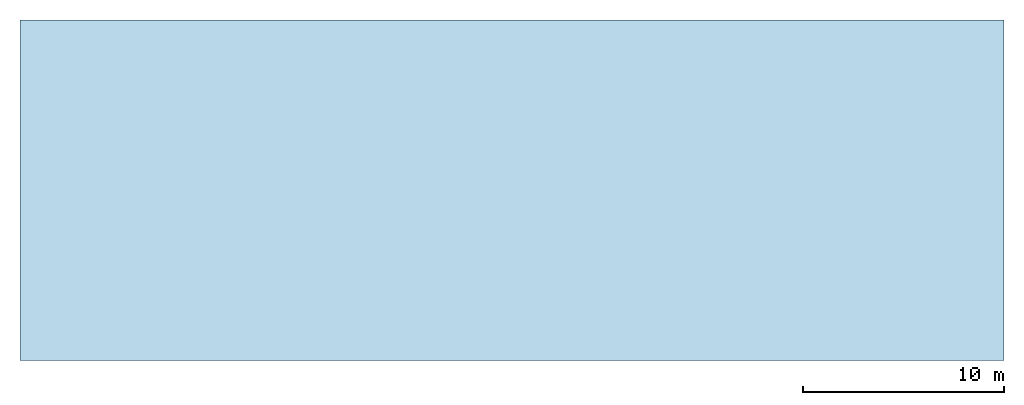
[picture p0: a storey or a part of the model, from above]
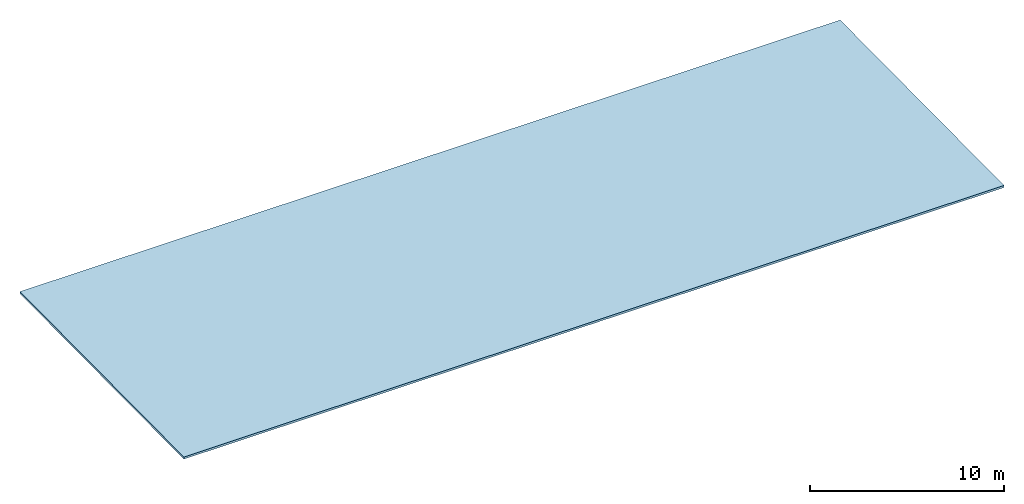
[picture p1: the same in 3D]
Properties of the parts of a building model (IFC4X3)

# File
Description: ViewDefinition [CoordinationView], RevitIdentifiers [VersionGUID: 392d5d86-4136-4b7f-a284-4d3e50420514, NumberOfSaves: 165], CoordinateReference [CoordinateBase: 共有座標, ProjectSite: 内部]
File name: 住木サンプルプラン3F_意匠_V24.ifc
Time: 2025-03-14T09:34:59+09:00
Written by: IfcOpenShell 0.8.0
Made in: Bonsai 0.8.0

# IfcProject, 123456
LongName: 標準参考テンプレート

# IfcSite, Default
RefLatitude: 35, 40, 59, 165954; RefLongitude: 139, 48, 33, 134765; RefElevation: 0 mm
Pset_SiteCommon - Reference: プロジェクト情報
Pset_SpaceCommon - Reference: プロジェクト情報; IsExternal: no

# IfcBuilding, 事務所ビル
LongName: 事務所ビル
Pset_BuildingCommon - Reference: プロジェクト情報; NumberOfStoreys: 6; IsLandmarked: no
Pset_BuildingElementProxyCommon - Reference: プロジェクト情報; IsExternal: no; sets with these values: 2
Pset_BuildingStoreyCommon - Reference: プロジェクト情報; AboveGround: no
Pset_BuildingSystemCommon - Reference: プロジェクト情報

# IfcBuildingStorey: レベル:標準上表記 (5)
In: 事務所ビル
Pset_BuildingStoreyCommon - AboveGround: no; Reference: 標準上表記
Pset_SpaceCommon - IsExternal: no; Reference: 標準上表記
Name | LongName | Elevation (mm)
1FL | 1FL | 0
2FL | 2FL | 4300
3FL | 3FL | 8000
RFL | RFL | 11470
最高高さ | 最高高さ | 12320

# IfcBuildingStorey: レベル:標準下表記, 設計GL
In: 事務所ビル
LongName: 設計GL; Elevation: -100 mm
Pset_BuildingStoreyCommon - Reference: 標準下表記; AboveGround: no
Pset_SpaceCommon - IsExternal: no; Reference: 標準下表記

# IfcSpace: EVホール 100:10737719, 100
In: 2FL
LongName: EVホール
Pset_SpaceCommon - IsExternal: no
Qto_SpaceBaseQuantities - NetPlannedArea: 17.3901 m2; Height: 2200 mm; FinishCeilingHeight: 670.56 mm
Pset_SpaceOccupancyRequirements - OccupancyType: 廊下
Pset_SpaceHVACDesign - MechanicalVentilation: no; HotWaterPresence: no; AirConditioning: no
Pset_SpaceLightingDesign - LightingFixtures: FRS15-322; NumberOfLightingFixtures: 3

# IfcSpace: EVホール 109:10737771, 109
In: 3FL
LongName: EVホール
Pset_SpaceCommon - IsExternal: no
Qto_SpaceBaseQuantities - NetPlannedArea: 17.3901 m2; Height: 2200 mm; FinishCeilingHeight: 670.56 mm
Pset_SpaceOccupancyRequirements - OccupancyType: 廊下
Pset_SpaceHVACDesign - MechanicalVentilation: no; HotWaterPresence: no; AirConditioning: no
Pset_SpaceLightingDesign - LightingFixtures: FRS15-322; NumberOfLightingFixtures: 3

# IfcSpace: EVホール 88:10716242, 88
In: 1FL
LongName: EVホール
Pset_SpaceCommon - IsExternal: no
Qto_SpaceBaseQuantities - NetPlannedArea: 17.3901 m2; Height: 2850 mm; FinishCeilingHeight: 868.68 mm
Pset_SpaceOccupancyRequirements - OccupancyType: 廊下
Pset_SpaceHVACDesign - MechanicalVentilation: no; HotWaterPresence: no; AirConditioning: no
Pset_SpaceLightingDesign - LightingFixtures: FRS15-322; NumberOfLightingFixtures: 3

# IfcSpace: WC 102:10737725, 102
In: 2FL
LongName: WC
Pset_SpaceCommon - IsExternal: no
Qto_SpaceBaseQuantities - NetPlannedArea: 14.9058 m2; Height: 2200 mm; FinishCeilingHeight: 670.56 mm
Pset_SpaceOccupancyRequirements - OccupancyType: 便所
Pset_SpaceHVACDesign - HotWaterPresence: no; AirConditioning: no; MechanicalVentilation: yes; VentilationName: FE-3
Pset_SpaceLightingDesign - LightingFixtures: FRS23-H321; NumberOfLightingFixtures: 7

# IfcSpace: WC 103:10737728, 103
In: 2FL
LongName: WC
Pset_SpaceCommon - IsExternal: no
Qto_SpaceBaseQuantities - NetPlannedArea: 14.9058 m2; Height: 2200 mm; FinishCeilingHeight: 670.56 mm
Pset_SpaceOccupancyRequirements - OccupancyType: 便所
Pset_SpaceHVACDesign - HotWaterPresence: no; AirConditioning: no; MechanicalVentilation: yes; VentilationName: FE-3
Pset_SpaceLightingDesign - LightingFixtures: FRS23-H321; NumberOfLightingFixtures: 7

# IfcSpace: WC 111:10737777, 111
In: 3FL
LongName: WC
Pset_SpaceCommon - IsExternal: no
Qto_SpaceBaseQuantities - NetPlannedArea: 14.9058 m2; Height: 2200 mm; FinishCeilingHeight: 670.56 mm
Pset_SpaceOccupancyRequirements - OccupancyType: 便所
Pset_SpaceHVACDesign - HotWaterPresence: no; AirConditioning: no; MechanicalVentilation: yes; VentilationName: FE-3
Pset_SpaceLightingDesign - LightingFixtures: FRS23-H321; NumberOfLightingFixtures: 7

# IfcSpace: WC 112:10737780, 112
In: 3FL
LongName: WC
Pset_SpaceCommon - IsExternal: no
Qto_SpaceBaseQuantities - NetPlannedArea: 14.9058 m2; Height: 2200 mm; FinishCeilingHeight: 670.56 mm
Pset_SpaceOccupancyRequirements - OccupancyType: 便所
Pset_SpaceHVACDesign - HotWaterPresence: no; AirConditioning: no; MechanicalVentilation: yes; VentilationName: FE-3
Pset_SpaceLightingDesign - LightingFixtures: FRS23-H321; NumberOfLightingFixtures: 7

# IfcSpace: WC 89:10716245, 89
In: 1FL
LongName: WC
Pset_SpaceCommon - IsExternal: no
Qto_SpaceBaseQuantities - NetPlannedArea: 14.9058 m2; Height: 2850 mm; FinishCeilingHeight: 868.68 mm
Pset_SpaceOccupancyRequirements - OccupancyType: 便所
Pset_SpaceHVACDesign - HotWaterPresence: no; AirConditioning: no; MechanicalVentilation: yes; VentilationName: FE-3
Pset_SpaceLightingDesign - LightingFixtures: FRS23-H321; NumberOfLightingFixtures: 7

# IfcSpace: WC 90:10716712, 90
In: 1FL
LongName: WC
Pset_SpaceCommon - IsExternal: no; Reference: WC 90
Qto_SpaceBaseQuantities - NetPlannedArea: 14.9058 m2; Height: 2850 mm; FinishCeilingHeight: 868.68 mm
Pset_SpaceOccupancyRequirements - OccupancyType: 便所
Pset_SpaceHVACDesign - HotWaterPresence: no; AirConditioning: no; MechanicalVentilation: yes; VentilationName: FE-3
Pset_SpaceLightingDesign - LightingFixtures: FRS23-H321; NumberOfLightingFixtures: 7

# IfcSpace: ロビー 91:10716755, 91
In: 1FL
LongName: ロビー
Pset_SpaceCommon - IsExternal: no
Qto_SpaceBaseQuantities - NetPlannedArea: 79.4976 m2; Height: 3280 mm; FinishCeilingHeight: 999.744 mm
Pset_SpaceOccupancyRequirements - OccupancyType: ロビー
Pset_SpaceHVACDesign - AirConditioning: yes; MechanicalVentilation: no; HotWaterPresence: no; AirHandlingName: PAC-1-4
Pset_SpaceLightingDesign - LightingFixtures: FRS15-322; NumberOfLightingFixtures: 11

# IfcSpace: 事務室 105:10737753, 105
In: 3FL
LongName: 事務室
Pset_SpaceCommon - IsExternal: no
Qto_SpaceBaseQuantities - NetPlannedArea: 700.573 m2; Height: 2680 mm; FinishCeilingHeight: 816.864 mm
Pset_SpaceOccupancyRequirements - OccupancyType: 事務室
Pset_SpaceHVACDesign - AirConditioning: yes; MechanicalVentilation: no; HotWaterPresence: yes; AirHandlingName: PAC-3-1
Pset_SpaceLightingDesign - LightingFixtures: FRS18L3V-322; NumberOfLightingFixtures: 169

# IfcSpace: 事務室 113:10955985, 113
In: 2FL
LongName: 事務室
Pset_SpaceCommon - IsExternal: no
Qto_SpaceBaseQuantities - NetPlannedArea: 274.414 m2; Height: 2680 mm; FinishCeilingHeight: 816.864 mm
Pset_SpaceOccupancyRequirements - OccupancyType: 事務室
Pset_SpaceHVACDesign - AirConditioning: yes; MechanicalVentilation: yes; HotWaterPresence: yes; AirHandlingName: PAC-2-2
Pset_SpaceLightingDesign - LightingFixtures: FRS18L3V-322; NumberOfLightingFixtures: 65

# IfcSpace: 事務室 94:10737700, 94
In: 2FL
LongName: 事務室
Pset_SpaceCommon - IsExternal: no
Qto_SpaceBaseQuantities - NetPlannedArea: 188.236 m2; Height: 2680 mm; FinishCeilingHeight: 816.864 mm
Pset_SpaceOccupancyRequirements - OccupancyType: 事務室
Pset_SpaceHVACDesign - AirConditioning: yes; MechanicalVentilation: no; HotWaterPresence: yes; AirHandlingName: PAC-2-3
Pset_SpaceLightingDesign - LightingFixtures: FRS18L3V-322; NumberOfLightingFixtures: 42

# IfcSpace: 事務室 96:10737707, 96
In: 2FL
LongName: 事務室
Pset_SpaceCommon - IsExternal: no
Qto_SpaceBaseQuantities - NetPlannedArea: 188.236 m2; Height: 2680 mm; FinishCeilingHeight: 816.864 mm
Pset_SpaceOccupancyRequirements - OccupancyType: 事務室
Pset_SpaceHVACDesign - AirConditioning: yes; MechanicalVentilation: no; HotWaterPresence: yes; AirHandlingName: PAC-2-1
Pset_SpaceLightingDesign - LightingFixtures: FRS18L3V-322; NumberOfLightingFixtures: 42

# IfcSpace: 倉庫 87:10716239, 87
In: 1FL
LongName: 倉庫
Pset_SpaceCommon - IsExternal: no
Qto_SpaceBaseQuantities - NetPlannedArea: 14.9058 m2; Height: 2850 mm; FinishCeilingHeight: 868.68 mm
Pset_SpaceOccupancyRequirements - OccupancyType: 更衣室又は倉庫
Pset_SpaceHVACDesign - HotWaterPresence: no; AirConditioning: no; MechanicalVentilation: yes; VentilationName: FE-3
Pset_SpaceLightingDesign - LightingFixtures: FRS23-H321; NumberOfLightingFixtures: 2

# IfcSpace: 店舗 82:10716224, 82
In: 1FL
LongName: 店舗
Pset_SpaceCommon - IsExternal: no
Qto_SpaceBaseQuantities - NetPlannedArea: 188.236 m2; Height: 3280 mm; FinishCeilingHeight: 999.744 mm
Pset_SpaceOccupancyRequirements - OccupancyType: 事務室
Pset_SpaceHVACDesign - AirConditioning: yes; MechanicalVentilation: no; HotWaterPresence: no; AirHandlingName: PAC-1-1
Pset_SpaceLightingDesign - LightingFixtures: FRS18L3V-322; NumberOfLightingFixtures: 42

# IfcSpace: 店舗 83:10716227, 83
In: 1FL
LongName: 店舗
Pset_SpaceCommon - IsExternal: no; Reference: 店舗 83
Pset_SpaceCoveringRequirements - FloorCovering: 大判タイル; WallCovering: 石こうボード t15; CeilingCovering: ロックウール化粧吸音板
Pset_SpaceHeaterTypeCommon - Reference: 店舗 83
Qto_SpaceBaseQuantities - NetPlannedArea: 200.971 m2; Height: 3280 mm; FinishCeilingHeight: 999.744 mm
Pset_SpaceOccupancyRequirements - OccupancyType: 事務室
Pset_SpaceHVACDesign - AirConditioning: yes; MechanicalVentilation: no; HotWaterPresence: no; AirHandlingName: PAC-1-2
Pset_SpaceLightingDesign - LightingFixtures: FRS18L3V-322; NumberOfLightingFixtures: 46

# IfcSpace: 店舗 84:10716230, 84
In: 1FL
LongName: 店舗
Pset_SpaceCommon - IsExternal: no; Reference: 店舗 84
Pset_SpaceCoveringRequirements - FloorCovering: 大判タイル; WallCovering: 石こうボード t15; CeilingCovering: ロックウール化粧吸音板
Pset_SpaceHeaterTypeCommon - Reference: 店舗 84
Qto_SpaceBaseQuantities - NetPlannedArea: 182.182 m2; Height: 3280 mm; FinishCeilingHeight: 999.744 mm
Pset_SpaceOccupancyRequirements - OccupancyType: 事務室
Pset_SpaceHVACDesign - AirConditioning: yes; MechanicalVentilation: no; HotWaterPresence: no; AirHandlingName: PAC-1-3
Pset_SpaceLightingDesign - LightingFixtures: FRS18L3V-322; NumberOfLightingFixtures: 42

# IfcSpace: 廊下 104:10737731, 104
In: 2FL
LongName: 廊下
Pset_SpaceCommon - IsExternal: no
Qto_SpaceBaseQuantities - NetPlannedArea: 49.686 m2; Height: 2200 mm; FinishCeilingHeight: 670.56 mm
Pset_SpaceOccupancyRequirements - OccupancyType: 廊下
Pset_SpaceHVACDesign - MechanicalVentilation: no; HotWaterPresence: no; AirConditioning: no
Pset_SpaceLightingDesign - LightingFixtures: FRS15-321; NumberOfLightingFixtures: 5

# IfcSpace: 廊下 86:10716236, 86
In: 1FL
LongName: 廊下
Pset_SpaceCommon - IsExternal: no
Qto_SpaceBaseQuantities - NetPlannedArea: 49.686 m2; Height: 2850 mm; FinishCeilingHeight: 868.68 mm
Pset_SpaceOccupancyRequirements - OccupancyType: 廊下
Pset_SpaceHVACDesign - MechanicalVentilation: no; HotWaterPresence: no; AirConditioning: no
Pset_SpaceLightingDesign - LightingFixtures: FRS15-321; NumberOfLightingFixtures: 5

# IfcSpace: 機械室 106:10737762, 106
In: 3FL
LongName: 機械室
Pset_SpaceCommon - IsExternal: no
Qto_SpaceBaseQuantities - NetPlannedArea: 29.8116 m2; Height: 2870 mm; FinishCeilingHeight: 874.776 mm
Pset_SpaceOccupancyRequirements - OccupancyType: 機械室
Pset_SpaceHVACDesign - HotWaterPresence: no; AirConditioning: no; MechanicalVentilation: yes; VentilationName: FS-1
Pset_SpaceLightingDesign - LightingFixtures: FRS23-H321; NumberOfLightingFixtures: 1

# IfcSpace: 機械室 85:10716233, 85
In: 1FL
LongName: 機械室
Pset_SpaceCommon - IsExternal: no
Qto_SpaceBaseQuantities - NetPlannedArea: 29.8116 m2; Height: 2850 mm; FinishCeilingHeight: 868.68 mm
Pset_SpaceOccupancyRequirements - OccupancyType: 機械室
Pset_SpaceHVACDesign - HotWaterPresence: no; AirConditioning: no; MechanicalVentilation: yes; VentilationName: FS-1
Pset_SpaceLightingDesign - LightingFixtures: FRS23-H321; NumberOfLightingFixtures: 1

# IfcSpace: 機械室 97:10737710, 97
In: 2FL
LongName: 機械室
Pset_SpaceCommon - IsExternal: no
Qto_SpaceBaseQuantities - NetPlannedArea: 29.8116 m2; Height: 2870 mm; FinishCeilingHeight: 874.776 mm
Pset_SpaceOccupancyRequirements - OccupancyType: 機械室
Pset_SpaceHVACDesign - HotWaterPresence: no; AirConditioning: no; MechanicalVentilation: yes; VentilationName: FS-1
Pset_SpaceLightingDesign - LightingFixtures: FRS23-H321; NumberOfLightingFixtures: 1

# IfcSpace: 給湯 107:10737765, 107
In: 3FL
LongName: 給湯
Pset_SpaceCommon - IsExternal: no
Qto_SpaceBaseQuantities - NetPlannedArea: 14.9058 m2; Height: 2200 mm; FinishCeilingHeight: 670.56 mm
Pset_SpaceOccupancyRequirements - OccupancyType: 湯沸室等
Pset_SpaceHVACDesign - HotWaterPresence: no; AirConditioning: no; MechanicalVentilation: yes; VentilationName: FE-2
Pset_SpaceLightingDesign - LightingFixtures: FRS23-H321; NumberOfLightingFixtures: 1

# IfcSpace: 給湯 98:10737713, 98
In: 2FL
LongName: 給湯
Pset_SpaceCommon - IsExternal: no
Qto_SpaceBaseQuantities - NetPlannedArea: 14.9058 m2; Height: 2200 mm; FinishCeilingHeight: 670.56 mm
Pset_SpaceOccupancyRequirements - OccupancyType: 湯沸室等
Pset_SpaceHVACDesign - HotWaterPresence: no; AirConditioning: no; MechanicalVentilation: yes; VentilationName: FE-2
Pset_SpaceLightingDesign - LightingFixtures: FRS23-H321; NumberOfLightingFixtures: 1

# IfcSpace: 階段 101:10737722, 101
In: 2FL
LongName: 階段
Pset_SpaceCommon - IsExternal: no
Qto_SpaceBaseQuantities - NetPlannedArea: 14.9058 m2; Height: 3700 mm
Pset_SpaceHVACDesign - MechanicalVentilation: no; HotWaterPresence: no; AirConditioning: no

# IfcSpace: 階段 108:10737768, 108
In: 3FL
LongName: 階段
Pset_SpaceCommon - IsExternal: no
Qto_SpaceBaseQuantities - NetPlannedArea: 14.9058 m2; Height: 2200 mm
Pset_SpaceHVACDesign - MechanicalVentilation: no; HotWaterPresence: no; AirConditioning: no

# IfcSpace: 階段 110:10737774, 110
In: 3FL
LongName: 階段
Pset_SpaceCommon - IsExternal: no
Qto_SpaceBaseQuantities - NetPlannedArea: 14.9058 m2; Height: 2200 mm
Pset_SpaceHVACDesign - MechanicalVentilation: no; HotWaterPresence: no; AirConditioning: no

# IfcSpace: 階段 92:10719681, 92
In: 1FL
LongName: 階段
Pset_SpaceCommon - IsExternal: no
Qto_SpaceBaseQuantities - NetPlannedArea: 14.9058 m2; Height: 4300 mm
Pset_SpaceHVACDesign - MechanicalVentilation: no; HotWaterPresence: no; AirConditioning: no

# IfcSpace: 階段 93:10719684, 93
In: 1FL
LongName: 階段
Pset_SpaceCommon - IsExternal: no
Qto_SpaceBaseQuantities - NetPlannedArea: 14.9058 m2; Height: 4300 mm
Pset_SpaceHVACDesign - MechanicalVentilation: no; HotWaterPresence: no; AirConditioning: no

# IfcSpace: 階段 99:10737716, 99
In: 2FL
LongName: 階段
Pset_SpaceCommon - IsExternal: no
Qto_SpaceBaseQuantities - NetPlannedArea: 14.9058 m2; Height: 3700 mm
Pset_SpaceHVACDesign - MechanicalVentilation: no; HotWaterPresence: no; AirConditioning: no

# IfcCovering: 天井:(仕上)GB-Rt12.5+DR t12 (38)
Type - PredefinedType: CEILING
Type - Pset_CoveringCommon - IsExternal: no
Material: <Unnamed> 10 mm
Name (天井:(仕上)GB-Rt12.5+DR t12:...) | In | Pset_CoveringCommon, Reference = Pset_EnvironmentalImpactIndicators, Reference
10720730 | 1FL | (仕上)GB-Rt12.5+DR t12
10720965 | 82
10726489 | 83
10727184 | 84
10728089 | 91
10728653 | 1FL | (仕上)GB-Rt12.5+DR t12
10728711 | 1FL | (仕上)GB-Rt12.5+DR t12
10728745 | 1FL | (仕上)GB-Rt12.5+DR t12
10728777 | 86
10728810 | 85
10728850 | 87
10728890 | 88
10728924 | 1FL | (仕上)GB-Rt12.5+DR t12
10728957 | 90
10728990 | 89
10729932 | 2FL | (仕上)GB-Rt12.5+DR t12
10729939 | 94
10729950 | 2FL | (仕上)GB-Rt12.5+DR t12
10729975 | 2FL | (仕上)GB-Rt12.5+DR t12
10729982 | 2FL | (仕上)GB-Rt12.5+DR t12
10729996 | 104
10730003 | 2FL | (仕上)GB-Rt12.5+DR t12
10730010 | 98 | (仕上)GB-Rt12.5+DR t12
10730017 | 100 | (仕上)GB-Rt12.5+DR t12
10730024 | 2FL | (仕上)GB-Rt12.5+DR t12
10730031 | 102 | (仕上)GB-Rt12.5+DR t12
10730038 | 103 | (仕上)GB-Rt12.5+DR t12
10730186 | 96
10733353 | 3FL | (仕上)GB-Rt12.5+DR t12
10733360 | 3FL | (仕上)GB-Rt12.5+DR t12
10733371 | 3FL | (仕上)GB-Rt12.5+DR t12
10733399 | 3FL | (仕上)GB-Rt12.5+DR t12
10733406 | 107 | (仕上)GB-Rt12.5+DR t12
10733413 | 109 | (仕上)GB-Rt12.5+DR t12
10733420 | 3FL | (仕上)GB-Rt12.5+DR t12
10733427 | 111 | (仕上)GB-Rt12.5+DR t12
10733434 | 112 | (仕上)GB-Rt12.5+DR t12
10733441 | 3FL | (仕上)GB-Rt12.5+DR t12

# IfcDoor: シャッター - 上下開閉式:シャッター - 上下開閉式 H2200 (3)
Type - PredefinedType: DOOR; ParameterTakesPrecedence: no; Material: <Unnamed>
Type - Pset_DoorCommon - IsExternal: no; HasLouver: no
OverallHeight: 2200 mm; OverallWidth: 1530 mm
Name (シャッター - 上下開閉式:シャッター - 上下開閉式 H2200:...) | In
10780350 | 1FL
10780501 | 1FL
10780597 | 2FL

# IfcDoor: ドア-開口部:1017 x 2100mm (3)
Type - PredefinedType: DOOR; ParameterTakesPrecedence: no; Material: <Unnamed>
Type - Pset_DoorCommon - IsExternal: no; HasLouver: no
OverallHeight: 2100 mm; OverallWidth: 1017 mm
Pset_DoorCommon - Reference: 1017 x 2100mm
Pset_EnvironmentalImpactIndicators - Reference: 1017 x 2100mm
Name (ドア-開口部:1017 x 2100mm:...) | In
10718628 | 1FL
10729121 | 2FL
10731907 | 3FL

# IfcDoor: ドア-開口部:2275 x 2100mm (3)
Type - PredefinedType: DOOR; ParameterTakesPrecedence: no; Material: <Unnamed>
Type - Pset_DoorCommon - IsExternal: no; HasLouver: no
OverallHeight: 2100 mm; OverallWidth: 2275 mm
Pset_DoorCommon - Reference: 2275 x 2100mm
Pset_EnvironmentalImpactIndicators - Reference: 2275 x 2100mm
Name (ドア-開口部:2275 x 2100mm:...) | In
10718684 | 1FL
10729122 | 2FL
10731908 | 3FL

# IfcDoor: 自動ドア - 両引き - 框:鋼製戸 - 両引き - 框, 自動ドア - 両引き - 框:鋼製戸 - 両引き - 框:10703156
In: 1FL
Type - PredefinedType: DOOR; ParameterTakesPrecedence: no; Material: <Unnamed> (2), ガラス
Type - Pset_DoorCommon - IsExternal: no; HasLouver: no
OverallHeight: 2440 mm; OverallWidth: 5280 mm; Material: <Unnamed>, ガラス

# IfcDoor: 自動ドア - 片引き - 框:自動ドア - 片引き - 框 (3)
In: 1FL
Type - PredefinedType: DOOR; ParameterTakesPrecedence: no; Material: <Unnamed> (2), ガラス
Type - Pset_DoorCommon - IsExternal: no; ThermalTransmittance: 3.6886 kg/K/s3; HasLouver: no
Type - Pset_DoorWindowGlazingType - SolarHeatGainTransmittance: 0.78 kg/K/s3
Material: <Unnamed>, ガラス
Name (自動ドア - 片引き - 框:自動ドア - 片引き - 框:...) | OverallHeight (mm) | OverallWidth (mm)
10702319 | 2040 | 1680
10962794 | 2440 | 3480
10963158 | 2440 | 3480

# IfcDoor: 鋼製_一般枠_片開き 1:鋼製_一般枠_片開き 1 (6)
Type - PredefinedType: DOOR; OperationType: SINGLE_SWING_LEFT; ParameterTakesPrecedence: no; Material: 金属 - アルミニウム (2), 塗装 - 白, ガラス
Type - 鋼製_一般枠_片開き 1:鋼製_一般枠_片開き 1:10708855:1 - PanelOperation: SWINGING
Type - Pset_DoorCommon - IsExternal: no; HasLouver: no
OverallHeight: 2140 mm; OverallWidth: 980 mm; Material: 金属 - アルミニウム, 塗装 - 白, ガラス
Name (鋼製_一般枠_片開き 1:鋼製_一般枠_片開き 1:...) | In
10708855 | 1FL
10709950 | 1FL
10729116 | 2FL
10729119 | 2FL
10731902 | 3FL
10731905 | 3FL

# IfcDoor: 鋼製_一般枠_片開き 1:鋼製_一般枠_片開き 1 (6)
Type - PredefinedType: DOOR; OperationType: SINGLE_SWING_RIGHT; ParameterTakesPrecedence: no; Material: 金属 - アルミニウム (2), 塗装 - 白, ガラス
Type - 鋼製_一般枠_片開き 1:鋼製_一般枠_片開き 1:10709358:1 - PanelOperation: SWINGING
Type - Pset_DoorCommon - IsExternal: no; HasLouver: no
OverallHeight: 2140 mm; OverallWidth: 980 mm; Material: 金属 - アルミニウム, 塗装 - 白, ガラス
Name (鋼製_一般枠_片開き 1:鋼製_一般枠_片開き 1:...) | In
10709358 | 1FL
10709926 | 1FL
10729117 | 2FL
10729118 | 2FL | Pset_DoorCommon - Reference: 鋼製_一般枠_片開き 1; Pset_EnvironmentalImpactIndicators - Reference: 鋼製_一般枠_片開き 1
10731903 | 3FL
10731904 | 3FL

# IfcDoor: 鋼製_大枠_両開き_框:1400x2000 (14)
Type - PredefinedType: DOOR; ParameterTakesPrecedence: no; Material: ステンレス, 塗装 - 白 (2), ガラス
Type - 鋼製_大枠_両開き_框:1400x2000:10688236:1 - PanelOperation: SWINGING
Type - Pset_DoorCommon - IsExternal: no; HasLouver: no
OverallHeight: 2055 mm; OverallWidth: 1480 mm; Material: ステンレス, 塗装 - 白, ガラス
Name (鋼製_大枠_両開き_框:1400x2000:...) | In
10688236 | 1FL
10688547 | 1FL
10689308 | 1FL
10689426 | 1FL
10704238 | 1FL
10704292 | 1FL
10729101 | 2FL
10729102 | 2FL
10729103 | 2FL
10729104 | 2FL
10729112 | 2FL
10729113 | 2FL
10731898 | 3FL
10731899 | 3FL

# IfcDoor: 鋼製_大枠_両開き_框:1400x2000 (3)
In: 1FL
Type - PredefinedType: DOOR; ParameterTakesPrecedence: no; Material: ステンレス, 塗装 - 白 (2), ガラス
Type - 鋼製_大枠_両開き_框:1400x2000:10702580:1 - PanelOperation: SWINGING
Type - Pset_DoorCommon - IsExternal: no; HasLouver: no
OverallHeight: 2055 mm; OverallWidth: 1480 mm; Material: ステンレス, 塗装 - 白, ガラス
Name (鋼製_大枠_両開き_框:1400x2000:...)
10702580
10704753
10704847

# IfcDoor: 鋼製_大枠_両開き_框:1400x2000, 鋼製_大枠_両開き_框:1400x2000:10785605
In: 設計GL
Type - PredefinedType: DOOR; ParameterTakesPrecedence: no; Material: ステンレス, 塗装 - 白 (2), ガラス
Type - 鋼製_大枠_両開き_框:1400x2000:10785605:1 - PanelOperation: SWINGING
Type - Pset_DoorCommon - IsExternal: no; HasLouver: no
OverallHeight: 2055 mm; OverallWidth: 1480 mm; Material: ステンレス, 塗装 - 白, ガラス

# IfcDoor: 鋼製_大枠_片開き_窓付:700x2100, 鋼製_大枠_片開き_窓付:700x2100:10786122
In: 1FL
Type - PredefinedType: DOOR; OperationType: SINGLE_SWING_LEFT; ParameterTakesPrecedence: no; Material: ステンレス, 塗装 - 白 (2), ガラス
Type - 鋼製_大枠_片開き_窓付:700x2100:10786122:1 - PanelOperation: SWINGING
Type - Pset_DoorCommon - IsExternal: no; HasLouver: no
OverallHeight: 2155 mm; OverallWidth: 780 mm; Material: ステンレス, 塗装 - 白, ガラス

# IfcDoor: 鋼製_大枠_片開き_窓付:700x2100, 鋼製_大枠_片開き_窓付:700x2100:10785387
In: 1FL
Type - PredefinedType: DOOR; OperationType: SINGLE_SWING_RIGHT; ParameterTakesPrecedence: no; Material: ステンレス, 塗装 - 白 (2), ガラス
Type - 鋼製_大枠_片開き_窓付:700x2100:10785387:1 - PanelOperation: SWINGING
Type - Pset_DoorCommon - IsExternal: no; HasLouver: no
OverallHeight: 2155 mm; OverallWidth: 780 mm; Material: ステンレス, 塗装 - 白, ガラス

# IfcOpeningElement (178)
PredefinedType: OPENING
Name | In
標準壁:(基礎梁)RC_w240h1000:10638460 | 1FL | Pset_EnvironmentalImpactIndicators - Reference: 700x2100; sets with these values: 2
標準壁:(基礎梁)RC_w240h1000:10638760 | 1FL | Pset_EnvironmentalImpactIndicators - Reference: 1400x2000; sets with these values: 2
標準壁:(基礎梁)RC_w240h1000:10639040 | 1FL | Pset_EnvironmentalImpactIndicators - Reference: 1400x2000; sets with these values: 2
標準壁:(基礎梁)RC_w240h650:10640903:1 | 1FL | Pset_EnvironmentalImpactIndicators - Reference: (基礎梁)RC_w240h650; sets with these values: 2
標準壁:(基礎梁)RC_w210h650:10643982:1 | 1FL | Pset_EnvironmentalImpactIndicators - Reference: (基礎梁)RC_w210h650; sets with these values: 2
標準壁:(基礎梁)RC_w210h650:10644302:1 | 1FL | Pset_EnvironmentalImpactIndicators - Reference: (基礎梁)RC_w210h650; sets with these values: 2
標準壁:(基礎梁)RC_w210h650:10644448:1 | 1FL | Pset_EnvironmentalImpactIndicators - Reference: (基礎梁)RC_w210h650; sets with these values: 2
標準壁:(基礎梁)RC_w210h650:10644556:1 | 1FL | Pset_EnvironmentalImpactIndicators - Reference: (基礎梁)RC_w210h650; sets with these values: 2
標準壁:(基礎梁)RC_w210h650:10644740:1 | 1FL | Pset_EnvironmentalImpactIndicators - Reference: (基礎梁)RC_w210h650; sets with these values: 2
2 x 標準壁:(基礎梁)RC_w210h1000:10645130 | 1FL | Pset_EnvironmentalImpactIndicators - Reference: 6 人乗; sets with these values: 2
標準壁:外装材46_構造用合板12_木240_構造用合板12_GB-R15:10672847 | 1FL | Pset_EnvironmentalImpactIndicators - Reference: 1450x2700; sets with these values: 2
標準壁:外装材46_構造用合板12_木240_構造用合板12_GB-R15:10673549 | 1FL | Pset_EnvironmentalImpactIndicators - Reference: 鋼製戸 - 両引き - 框; sets with these values: 2
標準壁:外装材46_構造用合板12_木240_構造用合板12_GB-R15:10674468 | 1FL | Pset_EnvironmentalImpactIndicators - Reference: 1450x2700; sets with these values: 2
2 x 標準壁:外装材46_構造用合板12_木240_構造用合板12_GB-R15:10674640 | 1FL | Pset_EnvironmentalImpactIndicators - Reference: 700x2100; sets with these values: 2
標準壁:外装材46_構造用合板12_木240_構造用合板12_GB-R15:10674640 | 1FL | Pset_EnvironmentalImpactIndicators - Reference: 1400x2000; sets with these values: 2
標準壁:GB-R15_構造用合板12_木210_構造用合板12_GB-R15:10676044 | 1FL | Pset_EnvironmentalImpactIndicators - Reference: 1400x2000; sets with these values: 2
2 x 標準壁:GB-R15_構造用合板12_木210_構造用合板12_GB-R15:10676202 | 1FL | Pset_EnvironmentalImpactIndicators - Reference: 1400x2000; sets with these values: 2
標準壁:GB-R15_構造用合板12_木210_構造用合板12_GB-R15:10676344 | 1FL | Pset_EnvironmentalImpactIndicators - Reference: 1400x2000; sets with these values: 2
2 x 標準壁:GB-R15_構造用合板12_木210_構造用合板12_GB-R15:10677149 | 1FL | Pset_EnvironmentalImpactIndicators - Reference: 2275 x 2100mm; sets with these values: 2
5 x 床:タイル20_モルタル30_スラブ200:1092007 | 1FL | Pset_EnvironmentalImpactIndicators - Reference: タイル20_モルタル30_スラブ200; sets with these values: 2
標準壁:GB-R15_構造用合板12_木210_構造用合板12_GB-R15:10684239 | 1FL | Pset_EnvironmentalImpactIndicators - Reference: 鋼製_一般枠_片開き 1; sets with these values: 2
標準壁:GB-R15_構造用合板12_木210_構造用合板12_GB-R15:10684438 | 1FL | Pset_EnvironmentalImpactIndicators - Reference: 2275 x 2100mm; sets with these values: 2
2 x 標準壁:GB-R15_構造用合板12_木210_構造用合板12_GB-R15:10684519 | 1FL | Pset_EnvironmentalImpactIndicators - Reference: 鋼製_一般枠_片開き 1; sets with these values: 2
2 x 標準壁:(内壁)木210/構造用合板12/GB-R15)/*:10725627 | 1FL | Pset_EnvironmentalImpactIndicators - Reference: 6 人乗; sets with these values: 2
2 x 標準壁:GB-R15_構造用合板12_木210_構造用合板12_GB-R15:10729093 | 2FL | Pset_EnvironmentalImpactIndicators - Reference: 2275 x 2100mm; sets with these values: 2
標準壁:GB-R15_構造用合板12_木210_構造用合板12_GB-R15:10729097 | 2FL | Pset_EnvironmentalImpactIndicators - Reference: 鋼製_一般枠_片開き 1; sets with these values: 2
標準壁:GB-R15_構造用合板12_木210_構造用合板12_GB-R15:10729098 | 2FL | Pset_EnvironmentalImpactIndicators - Reference: 2275 x 2100mm; sets with these values: 2
5 x 床:複層床:10729757 | 2FL | Pset_EnvironmentalImpactIndicators - Reference: 複層床; sets with these values: 2
2 x 標準壁:外装材46_構造用合板12_木240_構造用合板12_GB-R15:10731865 | 3FL | Pset_EnvironmentalImpactIndicators - Reference: 1450x2600; sets with these values: 2
標準壁:外装材46_構造用合板12_木240_構造用合板12_GB-R15:10731869 | 3FL | Pset_EnvironmentalImpactIndicators - Reference: 1450x2600; sets with these values: 2
標準壁:GB-R15_構造用合板12_木210_構造用合板12_GB-R15:10731879 | 3FL | Pset_EnvironmentalImpactIndicators - Reference: 2275 x 2100mm; sets with these values: 2
2 x 床:複層床:10729757 | 3FL | Pset_EnvironmentalImpactIndicators - Reference: 複層床; sets with these values: 2
2 x 標準壁:(内壁)木210/構造用合板12/GB-R15)/*:10737047 | 2FL | Pset_EnvironmentalImpactIndicators - Reference: 6 人乗; sets with these values: 2
標準壁:外装材46_構造用合板12_木240_構造用合板12_GB-R15:10739789 | 3FL | Pset_EnvironmentalImpactIndicators - Reference: 540x2700; sets with these values: 2
標準壁:GB-R15:10970786:1 | 1FL | Pset_EnvironmentalImpactIndicators - Reference: GB-R15; sets with these values: 2
標準壁:GB-R15:10971127:1 | 2FL | Pset_EnvironmentalImpactIndicators - Reference: GB-R15; sets with these values: 2
自動ドア - 両引き - 框:鋼製戸 - 両引き - 框:10703156:1 | 1FL
鋼製_大枠_片開き_窓付:700x2100:10785387:1 | 1FL
鋼製_大枠_両開き_框:1400x2000:10785605:1 | 1FL
鋼製_大枠_片開き_窓付:700x2100:10786122:1 | 1FL
鋼製_大枠_両開き_框:1400x2000:10704753:1 | 1FL
鋼製_大枠_両開き_框:1400x2000:10704847:1 | 1FL
6 x 標準壁:外装材46_構造用合板12_木240_構造用合板12_GB-R15:10673549 | 1FL
自動ドア - 片引き - 框:自動ドア - 片引き - 框:10962794:1 | 1FL
自動ドア - 片引き - 框:自動ドア - 片引き - 框:10963158:1 | 1FL
自動ドア - 片引き - 框:自動ドア - 片引き - 框:10702319:1 | 1FL
鋼製_大枠_両開き_框:1400x2000:10702580:1 | 1FL
8 x 標準壁:外装材46_構造用合板12_木240_構造用合板12_GB-R15:10674640 | 1FL
シャッター - 上下開閉式:シャッター - 上下開閉式 H2200:10780350:1 | 1FL
シャッター - 上下開閉式:シャッター - 上下開閉式 H2200:10780501:1 | 1FL
鋼製_大枠_両開き_框:1400x2000:10688236:1 | 1FL
鋼製_大枠_両開き_框:1400x2000:10689308:1 | 1FL
鋼製_大枠_両開き_框:1400x2000:10689426:1 | 1FL
鋼製_大枠_両開き_框:1400x2000:10688547:1 | 1FL
鋼製_大枠_両開き_框:1400x2000:10704238:1 | 1FL
鋼製_大枠_両開き_框:1400x2000:10704292:1 | 1FL
ドア-開口部:1017 x 2100mm:10718628:1 | 1FL
鋼製_一般枠_片開き 1:鋼製_一般枠_片開き 1:10708855:1 | 1FL
ドア-開口部:2275 x 2100mm:10718684:1 | 1FL
鋼製_一般枠_片開き 1:鋼製_一般枠_片開き 1:10709358:1 | 1FL
鋼製_一般枠_片開き 1:鋼製_一般枠_片開き 1:10709926:1 | 1FL
鋼製_一般枠_片開き 1:鋼製_一般枠_片開き 1:10709950:1 | 1FL
3 x 標準壁:外装材46_構造用合板12_木240_構造用合板12_GB-R15:10729079 | 2FL
13 x 標準壁:外装材46_構造用合板12_木240_構造用合板12_GB-R15:10729082 | 2FL
3 x 標準壁:外装材46_構造用合板12_木240_構造用合板12_GB-R15:10729083 | 2FL
シャッター - 上下開閉式:シャッター - 上下開閉式 H2200:10780597:1 | 2FL
12 x 標準壁:外装材46_構造用合板12_木240_構造用合板12_GB-R15:10729086 | 2FL
鋼製_大枠_両開き_框:1400x2000:10729101:1 | 2FL
鋼製_大枠_両開き_框:1400x2000:10729103:1 | 2FL
鋼製_大枠_両開き_框:1400x2000:10729104:1 | 2FL
鋼製_大枠_両開き_框:1400x2000:10729102:1 | 2FL
鋼製_大枠_両開き_框:1400x2000:10729112:1 | 2FL
鋼製_大枠_両開き_框:1400x2000:10729113:1 | 2FL
ドア-開口部:1017 x 2100mm:10729121:1 | 2FL
鋼製_一般枠_片開き 1:鋼製_一般枠_片開き 1:10729116:1 | 2FL
ドア-開口部:2275 x 2100mm:10729122:1 | 2FL
鋼製_一般枠_片開き 1:鋼製_一般枠_片開き 1:10729117:1 | 2FL
鋼製_一般枠_片開き 1:鋼製_一般枠_片開き 1:10729118:1 | 2FL
鋼製_一般枠_片開き 1:鋼製_一般枠_片開き 1:10729119:1 | 2FL
4 x 標準壁:外装材46_構造用合板12_木240_構造用合板12_GB-R15:10731865 | 3FL
14 x 標準壁:外装材46_構造用合板12_木240_構造用合板12_GB-R15:10731868 | 3FL
4 x 標準壁:外装材46_構造用合板12_木240_構造用合板12_GB-R15:10731869 | 3FL
鋼製_大枠_両開き_框:1400x2000:10731898:1 | 3FL
鋼製_大枠_両開き_框:1400x2000:10731899:1 | 3FL
ドア-開口部:1017 x 2100mm:10731907:1 | 3FL
鋼製_一般枠_片開き 1:鋼製_一般枠_片開き 1:10731902:1 | 3FL
ドア-開口部:2275 x 2100mm:10731908:1 | 3FL
鋼製_一般枠_片開き 1:鋼製_一般枠_片開き 1:10731903:1 | 3FL
鋼製_一般枠_片開き 1:鋼製_一般枠_片開き 1:10731904:1 | 3FL
鋼製_一般枠_片開き 1:鋼製_一般枠_片開き 1:10731905:1 | 3FL
12 x 標準壁:外装材46_構造用合板12_木240_構造用合板12_GB-R15:10739789 | 3FL

# IfcSlab: 床:タイル20_モルタル30_スラブ200, 床:タイル20_モルタル30_スラブ200:10677755
In: 1FL
Type - PredefinedType: FLOOR; Material: <Unnamed> 200 mm
Type - Pset_SlabCommon - IsExternal: no
Type - Qto_SlabBaseQuantities - Depth: 200 mm
Qto_SlabBaseQuantities - NetArea: 804.585 m2; NetVolume: 160.917 m3

# IfcSlab: 床:複層床 (2)
Type - PredefinedType: FLOOR; Material: <Unnamed> 106 mm, 硬質ウレタンフォーム 100 mm, 合板 24 mm
Type - Pset_SlabCommon - IsExternal: no
Type - Qto_SlabBaseQuantities - Depth: 230 mm
Name (床:複層床:...) | In | NetArea (m2) | NetVolume (m3)
10729427 | 2FL | 771.885 | 177.534
10731914 | 3FL | 783.328 | 180.166

# IfcSlab: 標準屋根:(屋根)シート防水, 標準屋根:(屋根)シート防水:10733734
In: RFL
Type - Pset_SlabCommon - IsExternal: yes
Type - Qto_SlabBaseQuantities - Depth: 133.5 mm
Material: アスファルト類 3 mm, 硬質ウレタンフォーム 70 mm, 合板 12 mm, 非密閉中空層 30 mm, せっこうボード 9.5 mm, ロックウール化粧吸音板 9 mm; アスファルト類 3 mm, 硬質ウレタンフォーム 70 mm, 合板 12 mm, 非密閉中空層 30 mm, せっこうボード 9.5 mm, ロックウール化粧吸音板 9 mm
Pset_SlabCommon - Reference: (屋根)シート防水
Qto_SlabBaseQuantities - NetArea: 826.665 m2; NetVolume: 110.36 m3

# IfcWall: 標準壁:(内壁)木210/構造用合板12/GB-R15)/* (3)
Type - PredefinedType: STANDARD; Material: 天然木材 210 mm, <Unnamed> 12 mm, <Unnamed> 15 mm
Type - Pset_WallCommon - IsExternal: no; isExternal: no
Type - Qto_WallBaseQuantities - Width: 237 mm
Qto_WallBaseQuantities - Length: 5475.5 mm
Name (標準壁:(内壁)木210/構造用合板12/GB-R15)/*:...) | In | NetSideArea (m2) | NetVolume (m3)
10725627 | 1FL | 16.7481 | 3.9693
10731910 | 3FL | 17.9781 | 4.2608
10737047 | 2FL | 14.8983 | 3.5309

# IfcWall: 標準壁:(基礎梁)RC_w210h1000 (16)
In: 1FL
Type - PredefinedType: STANDARD; Material: *コンクリート 210 mm
Type - Pset_WallCommon - IsExternal: yes; isExternal: yes
Type - Qto_WallBaseQuantities - Width: 210 mm
Pset_EnvironmentalImpactIndicators - Reference: (基礎梁)RC_w210h1000; sets with these values: 2
Pset_WallCommon - ExtendToStructure: no; LoadBearing: yes; Reference: (基礎梁)RC_w210h1000
Name (標準壁:(基礎梁)RC_w210h1000:...) | NetSideArea (m2) | Length (mm) | NetVolume (m3)
10641416 | 5.38725 | 5460 | 1.13132
10641685 | 3.535 | 3640 | 0.74235
10641852 | 5.445 | 5565 | 1.14345
10642087 | 5.445 | 5460 | 1.14345
10642149 | 0.805 | 910 | 0.16905
10642448 | 5.445 | 5460 | 1.14345
10642514 | 0.805 | 910 | 0.16905
10645130 | 4.4214 | 5460 | 0.928494
10645255 | 3.85725 | 3810 | 0.810022
10645477 | 5.235 | 5460 | 1.09935
10645581 | 5.235 | 5460 | 1.09935
10645728 | 0.8995 | 910 | 0.188895
10645901 | 1.715 | 1820 | 0.36015
10646037 | 1.7 | 1820 | 0.357
10647090 | 1.82 | 1820 | 0.3822
10647203 | 5.445 | 5565 | 1.14345

# IfcWall: 標準壁:(基礎梁)RC_w210h650 (18)
In: 1FL
Type - PredefinedType: STANDARD; Material: *コンクリート 210 mm
Type - Pset_WallCommon - IsExternal: yes; isExternal: yes
Type - Qto_WallBaseQuantities - Width: 210 mm
Pset_EnvironmentalImpactIndicators - Reference: (基礎梁)RC_w210h650; sets with these values: 2
Pset_WallCommon - ExtendToStructure: no; Reference: (基礎梁)RC_w210h650; LoadBearing: yes
Name (標準壁:(基礎梁)RC_w210h650:...) | NetSideArea (m2) | Length (mm) | NetVolume (m3)
10640784 | 9.36925 | 17290 | 1.96754
10641139 | 0.935 | 1700 | 0.19635
10643982 | 9.23725 | 17290 | 1.93982
10644136 | 0.87725 | 1595 | 0.184223
10644302 | 6.358 | 11830 | 1.33518
10644448 | 6.2425 | 11695 | 1.31092
10644556 | 6.2425 | 11830 | 1.31092
10644740 | 6.2425 | 11725 | 1.31092
10644981 | 1.694 | 3185 | 0.35574
10646158 | 1.001 | 1820 | 0.21021
10646209 | 2.002 | 3640 | 0.42042
10646560 | 0.94325 | 1715 | 0.198082
10646683 | 0.94325 | 1820 | 0.198083
10646800 | 0.94325 | 1820 | 0.198082
10646946 | 0.94325 | 1715 | 0.198082
10648101 | 5.36525 | 9890 | 1.1267
10648556 | 5.36525 | 9890 | 1.1267
10648955 | 0.94325 | 1715 | 0.198082

# IfcWall: 標準壁:(基礎梁)RC_w240h1000 (13)
In: 1FL
Type - PredefinedType: STANDARD; Material: *コンクリート 240 mm
Type - Pset_WallCommon - IsExternal: yes; isExternal: yes
Type - Qto_WallBaseQuantities - Width: 240 mm
Pset_EnvironmentalImpactIndicators - Reference: (基礎梁)RC_w240h1000; sets with these values: 2
Pset_WallCommon - ExtendToStructure: no; Reference: (基礎梁)RC_w240h1000
Name (標準壁:(基礎梁)RC_w240h1000:...) | LoadBearing | NetSideArea (m2) | Length (mm) | NetVolume (m3)
10636491 | no | 4.84 | 4720 | 1.1616
10637143 | no | 3.98 | 3980 | 0.9552
10637334 | no | 5.495 | 5630 | 1.3188
10638460 | no | 19.122 | 19242 | 4.58928
10638760 | no | 1.95117 | 1952 | 0.468281
10639040 | no | 5.66717 | 5668 | 1.36012
10639310 | no | 19.362 | 19242 | 4.64688
10639575 | no | 4.52 | 4640 | 1.0848
10639878 | no | 3.86 | 3860 | 0.9264
10640052 | no | 5.495 | 5630 | 1.3188
10642780 | yes | 7.412 | 7337 | 1.77888
10643236 | yes | 9.1 | 9100 | 2.184
10643602 | yes | 7.415 | 7385 | 1.7796

# IfcWall: 標準壁:(基礎梁)RC_w240h650 (11)
In: 1FL
Type - PredefinedType: STANDARD; Material: *コンクリート 240 mm
Type - Pset_WallCommon - IsExternal: yes; isExternal: yes
Type - Qto_WallBaseQuantities - Width: 240 mm
Pset_EnvironmentalImpactIndicators - Reference: (基礎梁)RC_w240h650; sets with these values: 2
Pset_WallCommon - ExtendToStructure: no; Reference: (基礎梁)RC_w240h650
Name (標準壁:(基礎梁)RC_w240h650:...) | LoadBearing | NetSideArea (m2) | Length (mm) | NetVolume (m3)
10637004 | no | 0.814 | 1480 | 0.19536
10637220 | no | 0.814 | 1480 | 0.19536
10638875 | no | 0.7178 | 1480 | 0.172272
10639225 | no | 0.4279 | 778 | 0.102696
10639702 | no | 0.924 | 1680 | 0.22176
10639954 | no | 0.814 | 1480 | 0.19536
10640903 | yes | 5.76675 | 10815 | 1.38402
10642935 | yes | 1.001 | 1820 | 0.24024
10643403 | yes | 1.001 | 1820 | 0.24024
10643779 | yes | 5.88225 | 10815 | 1.41174
10649697 | no | 0.4279 | 778 | 0.102696

# IfcWall: 標準壁:(基礎梁)RC_w270h1000 (4)
In: 1FL
Type - PredefinedType: STANDARD; Material: *コンクリート 270 mm
Type - Pset_WallCommon - IsExternal: yes; isExternal: yes
Type - Qto_WallBaseQuantities - Width: 270 mm
Pset_EnvironmentalImpactIndicators - Reference: (基礎梁)RC_w270h1000; sets with these values: 2
Pset_WallCommon - Reference: (基礎梁)RC_w270h1000; LoadBearing: no; ExtendToStructure: no
Name (標準壁:(基礎梁)RC_w270h1000:...) | NetSideArea (m2) | Length (mm) | NetVolume (m3)
10636370 | 7.42 | 7300 | 2.0034
10637826 | 11.165 | 11060 | 3.01455
10638028 | 11.159 | 11165 | 3.01293
10638212 | 7.42 | 7300 | 2.0034

# IfcWall: 標準壁:(基礎梁)RC_w270h650 (3)
In: 1FL
Type - PredefinedType: STANDARD; Material: *コンクリート 270 mm
Type - Pset_WallCommon - IsExternal: yes; isExternal: yes
Type - Qto_WallBaseQuantities - Width: 270 mm
Pset_EnvironmentalImpactIndicators - Reference: (基礎梁)RC_w270h650; sets with these values: 2
Pset_WallCommon - LoadBearing: no; ExtendToStructure: no; Reference: (基礎梁)RC_w270h650
Name (標準壁:(基礎梁)RC_w270h650:...) | NetSideArea (m2) | Length (mm) | NetVolume (m3)
10637463 | 1.914 | 3480 | 0.51678
10637936 | 2.8875 | 5250 | 0.779625
10638101 | 1.914 | 3480 | 0.51678

# IfcWall: 標準壁:GB-R15 (21)
Type - PredefinedType: STANDARD; Material: <Unnamed> 15 mm
Type - Pset_WallCommon - IsExternal: no; isExternal: no
Type - Qto_WallBaseQuantities - Width: 15 mm
Pset_EnvironmentalImpactIndicators - Reference: GB-R15; sets with these values: 2
Pset_WallCommon - LoadBearing: no; ExtendToStructure: no; Reference: GB-R15
Name (標準壁:GB-R15:...) | In | NetSideArea (m2) | Length (mm) | NetVolume (m3)
10970113 | 1FL | 4.34962 | 10010 | 0.0652443
10970171 | 1FL | 1.2012 | 2730 | 0.018018
10970255 | 1FL | 4.34302 | 9953 | 0.0651453
10970586 | 1FL | 8.76788 | 20077 | 0.131518
10970710 | 1FL | 7.5779 | 17290 | 0.113668
10970786 | 1FL | 1.08504 | 2730 | 0.0162756
10970876 | 1FL | 4.34302 | 10010 | 0.0651453
10971123 | 2FL | 3.9542 | 10010 | 0.059313
10971124 | 2FL | 1.092 | 2730 | 0.01638
10971125 | 2FL | 3.9482 | 9953 | 0.059223
10971126 | 2FL | 8.0008 | 20077 | 0.120012
10971127 | 2FL | 6.859 | 17290 | 0.102885
10971128 | 2FL | 1.092 | 2730 | 0.01638
10971129 | 2FL | 3.9482 | 10010 | 0.059223
10971185 | 3FL | 3.9542 | 10010 | 0.059313
10971186 | 3FL | 1.092 | 2730 | 0.01638
10971187 | 3FL | 3.9782 | 9953 | 0.059673
10971188 | 3FL | 8.0308 | 20077 | 0.120462
10971189 | 3FL | 6.919 | 17290 | 0.103785
10971190 | 3FL | 1.092 | 2730 | 0.01638
10971191 | 3FL | 3.9482 | 10010 | 0.059223

# IfcWall: 標準壁:GB-R15_木120_GB-R15 (9)
Type - PredefinedType: STANDARD; Material: <Unnamed> 15 mm, 天然木材 120 mm, <Unnamed> 15 mm
Type - Pset_WallCommon - IsExternal: no; isExternal: no
Type - Qto_WallBaseQuantities - Width: 150 mm
Name (標準壁:GB-R15_木120_GB-R15:...) | In | NetSideArea (m2) | Length (mm) | NetVolume (m3)
10689821 | 1FL | 41.8997 | 10010 | 6.28496
10689910 | 1FL | 41.8997 | 10010 | 6.28496
10710089 | 1FL | 20.2059 | 5475.5 | 3.03089
10719454 | 1FL | 9.6174 | 2730 | 1.44261 | Pset_EnvironmentalImpactIndicators - Reference: GB-R15_木120_GB-R15; sets with these values: 2; Pset_WallCommon - LoadBearing: no; ExtendToStructure: no; Reference: GB-R15_木120_GB-R15
10729105 | 2FL | 36.0047 | 10025.5 | 5.4007
10729106 | 2FL | 36.0047 | 10025.5 | 5.4007
10731906 | 3FL | 17.9781 | 5475.5 | 2.69671
10731909 | 3FL | 8.55702 | 2730 | 1.28355 | Pset_EnvironmentalImpactIndicators - Reference: GB-R15_木120_GB-R15; sets with these values: 2; Pset_WallCommon - LoadBearing: no; ExtendToStructure: no; Reference: GB-R15_木120_GB-R15
10737239 | 2FL | 19.1697 | 5475.5 | 2.87546

# IfcWall: 標準壁:GB-R15_構造用合板12_木210_構造用合板12_GB-R15 (41)
Type - PredefinedType: STANDARD; Material: せっこうボード 15 mm, 合板 12 mm, 天然木材 210 mm, 合板 12 mm, せっこうボード 15 mm
Type - Pset_WallCommon - IsExternal: no; isExternal: no
Type - Qto_WallBaseQuantities - Width: 264 mm
Name (標準壁:GB-R15_構造用合板12_木210_構造用合板12_GB-R15:...) | In | NetSideArea (m2) | Length (mm) | NetVolume (m3)
10676044 | 1FL | 25.8841 | 7295.5 | 6.8334
10676202 | 1FL | 143.071 | 38292.5 | 37.7708
10676344 | 1FL | 24.8545 | 7295.5 | 6.56159
10676853 | 1FL | 26.057 | 8058 | 6.87905
10676975 | 1FL | 20.2059 | 5475.5 | 5.33436
10677077 | 1FL | 20.2059 | 5475.5 | 5.33436
10677149 | 1FL | 21.2355 | 5475.5 | 5.60617
10677218 | 1FL | 20.2059 | 5475.5 | 5.33436
10677343 | 1FL | 20.2059 | 5475.5 | 5.33436
10677431 | 1FL | 18.477 | 5475.5 | 4.87793
10684239 | 1FL | 9.4566 | 2730 | 2.49654
10684438 | 1FL | 16.3969 | 5328 | 4.32878
10684479 | 1FL | 9.9714 | 2862 | 2.63245 | Pset_EnvironmentalImpactIndicators - Reference: GB-R15_構造用合板12_木210_構造用合板12_GB-R15; sets with these values: 2; Pset_WallCommon - LoadBearing: no; ExtendToStructure: no; Reference: GB-R15_構造用合板12_木210_構造用合板12_GB-R15
10684519 | 1FL | 27.501 | 8058 | 7.26026
10729087 | 2FL | 23.8613 | 7295.5 | 6.29938
10729088 | 2FL | 94.9716 | 27357 | 25.0725
10729089 | 2FL | 22.8845 | 7295.5 | 6.04151
10729090 | 2FL | 23.2878 | 8058 | 6.14798
10729091 | 2FL | 19.1697 | 5475.5 | 5.0608
10729092 | 2FL | 19.1697 | 5475.5 | 5.0608
10729093 | 2FL | 20.1465 | 5475.5 | 5.31868
10729094 | 2FL | 19.1697 | 5475.5 | 5.0608
10729095 | 2FL | 19.1697 | 5475.5 | 5.0608
10729096 | 2FL | 17.034 | 5475.5 | 4.49698
10729097 | 2FL | 8.4922 | 2730 | 2.24194
10729098 | 2FL | 14.4477 | 5328 | 3.81419
10729099 | 2FL | 8.9806 | 2862 | 2.37088
10729100 | 2FL | 25.1318 | 8058 | 6.6348
10731873 | 3FL | 17.9781 | 5475.5 | 4.74621
10731875 | 3FL | 17.9781 | 5475.5 | 4.74621
10731876 | 3FL | 22.3809 | 8058 | 5.90856
10731877 | 3FL | 17.9781 | 5475.5 | 4.74621
10731878 | 3FL | 17.9781 | 5475.5 | 4.74621
10731879 | 3FL | 18.8942 | 5475.5 | 4.98806
10731880 | 3FL | 17.9781 | 5475.5 | 4.74621
10731881 | 3FL | 17.9781 | 5475.5 | 4.74621
10731882 | 3FL | 15.8424 | 5475.5 | 4.18239
10731883 | 3FL | 7.83394 | 2730 | 2.06816
10731884 | 3FL | 13.2526 | 5328 | 3.49869
10731885 | 3FL | 8.29198 | 2862 | 2.18908
10731886 | 3FL | 24.2249 | 8058 | 6.39537

# IfcWall: 標準壁:外装材46_構造用合板12_木240_構 (12)
Type - PredefinedType: STANDARD; Material: <Unnamed> 46 mm, 合板 12 mm, 天然木材 240 mm, 合板 12 mm, せっこうボード 15 mm
Type - Pset_WallCommon - IsExternal: no
Type - Qto_WallBaseQuantities - Width: 325 mm
Name (標準壁:外装材46_構造用合板12_木240_構造用合板12_GB-R15:...) | In | NetSideArea (m2) | Length (mm) | NetVolume (m3)
10672847 | 1FL | 62.6975 | 17321 | 20.3756
10673549 | 1FL | 143.104 | 49171 | 46.364
10674468 | 1FL | 62.3695 | 17321 | 20.269
10674640 | 1FL | 146.787 | 49171 | 47.5274
10729079 | 2FL | 52.5776 | 17321 | 16.9455
10729082 | 2FL | 132.056 | 49171 | 42.3016
10729083 | 2FL | 51.3751 | 17321 | 16.5547
10729086 | 2FL | 138.139 | 49171 | 44.3696
10731865 | 3FL | 63.203 | 17321 | 20.3535
10731868 | 3FL | 158.705 | 49171 | 50.9163
10731869 | 3FL | 61.799 | 17321 | 19.8862
10739789 | 3FL | 168.649 | 49171 | 54.2925

# IfcWindow: 鋼製_一般枠_2 段 1 列_嵌殺し+引違い: (33)
Type - PredefinedType: WINDOW; ParameterTakesPrecedence: no; Material: ガラス - 透明, 金属 - アルミニウム, 塗装 - 白
Type - Pset_WindowCommon - IsExternal: no; HasLouver: yes
OverallHeight: 2760 mm; OverallWidth: 1532 mm
Name (鋼製_一般枠_2 段 1 列_嵌殺し+引違い:1450x2600:...) | In
10758739 | 2FL
10758996 | 2FL
10759004 | 2FL
10759171 | 2FL
10759343 | 2FL
10759445 | 2FL
10759596 | 2FL
10759597 | 2FL
10759598 | 2FL
10759606 | 2FL
10759607 | 2FL
10759608 | 2FL
10759616 | 2FL
10759617 | 2FL
10759618 | 2FL
10759652 | 2FL
10789340 | 3FL
10789344 | 3FL
10789345 | 3FL
10789854 | 3FL
10789862 | 3FL
10790570 | 3FL
10790578 | 3FL
10790586 | 3FL
10790594 | 3FL
10790602 | 3FL
10790610 | 3FL
10790618 | 3FL
10790626 | 3FL
10790634 | 3FL
10790642 | 3FL
10790650 | 3FL
10790658 | 3FL

# IfcWindow: 鋼製_一般枠_2 段 1 列_嵌殺し+引違い:1450x2100, 鋼製_一般枠_2 段 1 列_嵌殺し+引違い:1450x2100:10849693
In: 2FL
Type - PredefinedType: WINDOW; ParameterTakesPrecedence: no; Material: ガラス - 透明, 金属 - アルミニウム, 塗装 - 白
Type - Pset_WindowCommon - IsExternal: no; HasLouver: yes
OverallHeight: 2260 mm; OverallWidth: 1532 mm

# IfcWindow: 鋼製_一般枠_2 段 1 列_嵌殺し+引違い:1450x2600 (19)
Type - PredefinedType: WINDOW; ParameterTakesPrecedence: no; Material: ガラス - 透明, 金属 - アルミニウム, 塗装 - 白
Type - Pset_WindowCommon - IsExternal: no; HasLouver: yes
OverallHeight: 2760 mm; OverallWidth: 1532 mm
Name (鋼製_一般枠_2 段 1 列_嵌殺し+引違い:1450x2600:...) | In
10759018 | 2FL
10759019 | 2FL
10759020 | 2FL
10759847 | 2FL
10759848 | 2FL
10759849 | 2FL
10759857 | 2FL
10759858 | 2FL
10759859 | 2FL
10790799 | 3FL
10790801 | 3FL
10790802 | 3FL
10966484 | 3FL
10966525 | 3FL
10966587 | 3FL
10967266 | 3FL
10967274 | 3FL
10967282 | 3FL
10967290 | 3FL

# IfcWindow: 鋼製_一般枠_嵌殺し:1450x2100 (10)
Type - PredefinedType: WINDOW; ParameterTakesPrecedence: no; Material: ガラス - 透明, 金属 - アルミニウム, 塗装 - 白
Type - Pset_WindowCommon - IsExternal: no; HasLouver: yes
OverallHeight: 2260 mm; OverallWidth: 1532 mm
Name (鋼製_一般枠_嵌殺し:1450x2100:...) | In
10759852 | 2FL
10759854 | 2FL
10759855 | 2FL
10764191 | 2FL
10850112 | 2FL
10967241 | 3FL
10967250 | 3FL
10967258 | 3FL
10967392 | 3FL
10967440 | 3FL

# IfcWindow: 鋼製_一般枠_嵌殺し:1450x2260 (2)
In: 1FL
Type - PredefinedType: WINDOW; ParameterTakesPrecedence: no; Material: ガラス - 透明, 金属 - アルミニウム, 塗装 - 白
Type - Pset_WindowCommon - IsExternal: no; HasLouver: yes
OverallHeight: 2420 mm; OverallWidth: 1532 mm
Name (鋼製_一般枠_嵌殺し:1450x2260:...)
10786487
10786649

# IfcWindow: 鋼製_一般枠_嵌殺し:1450x2700 (12)
In: 1FL
Type - PredefinedType: WINDOW; ParameterTakesPrecedence: no; Material: ガラス - 透明, 金属 - アルミニウム, 塗装 - 白
Type - Pset_WindowCommon - IsExternal: no; HasLouver: yes
OverallHeight: 2860 mm; OverallWidth: 1532 mm
Name (鋼製_一般枠_嵌殺し:1450x2700:...)
10778336
10778783
10778820
10786710
10786772
10786830
10788648
10788943
10788951
10788959
10788967
10788975

# IfcWindow: 鋼製_一般枠_嵌殺し:540x2700 (2)
In: 3FL
Type - PredefinedType: WINDOW; ParameterTakesPrecedence: no; Material: ガラス - 透明, 金属 - アルミニウム, 塗装 - 白
Type - Pset_WindowCommon - IsExternal: no; HasLouver: yes
OverallHeight: 2860 mm; OverallWidth: 622 mm
Name (鋼製_一般枠_嵌殺し:540x2700:...)
10789617
10790800 | Pset_EnvironmentalImpactIndicators - Reference: 540x2700; Pset_WindowCommon - Reference: 540x2700

# Material: *コンクリート
Identity - Class: 一般
その他 - カテゴリ: マテリアル
識別情報 - 価格: 0
マテリアルと仕上げ - グロー: no; フラットさ: 50; 光沢: 64; 名前: *コンクリート; 色: 11912385; 透過度: 0

# Material: 合板
Identity - Category: 一般; Class: 一般; Description: 82
その他 - カテゴリ: マテリアル; 建材番号: 82
識別情報 - コメント: 82; 価格: 0; 説明: 合板
マテリアルと仕上げ - グロー: no; 透過度: 0; フラットさ: 50; 光沢: 64; 名前: 合板; 色: 15000804

# Material: 天然木材
Identity - Category: 一般; Class: 木材; Description: 81
その他 - カテゴリ: マテリアル; 建材番号: 81
識別情報 - 価格: 0; 説明: 天然木材
マテリアルと仕上げ - グロー: no; 透過度: 0; フラットさ: 50; 光沢: 128; 名前: 天然木材; 色: 15000804

# Material: せっこうボード
Identity - Category: 一般; Class: 一般; Description: 61
その他 - カテゴリ: マテリアル; 建材番号: 61
識別情報 - コメント: 61; 価格: 0; 説明: 石膏ボード
マテリアルと仕上げ - グロー: no; 透過度: 0; フラットさ: 50; 光沢: 64; 名前: せっこうボード; 色: 15000804

# Material: ステンレス
Identity - Category: 未設定; Class: 未設定
その他 - カテゴリ: マテリアル
マテリアルと仕上げ - グロー: no; 透過度: 0; フラットさ: 50; 光沢: 128; 名前: ステンレス; 色: 16250871

# Material: 塗装 - 白
Identity - Category: 未設定; Class: 未設定
その他 - カテゴリ: マテリアル
マテリアルと仕上げ - グロー: no; 透過度: 0; フラットさ: 50; 光沢: 128; 名前: 塗装 - 白; 色: 16382457

# Material: ガラス
Identity - Category: ガラス; Class: ガラス
その他 - カテゴリ: マテリアル
識別情報 - 価格: 0
マテリアルと仕上げ - グロー: no; フラットさ: 50; 光沢: 64; 名前: ガラス; 色: 16711680; 透過度: 75

# Material: 金属 - アルミニウム
Identity - Category: 未設定; Class: 未設定
その他 - カテゴリ: マテリアル
マテリアルと仕上げ - グロー: no; 透過度: 0; フラットさ: 50; 光沢: 128; 名前: 金属 - アルミニウム; 色: 16250871

# Material: 塗装 - 白
Identity - Category: 未設定; Class: 未設定
その他 - カテゴリ: マテリアル
マテリアルと仕上げ - グロー: no; 透過度: 0; フラットさ: 50; 光沢: 128; 名前: 塗装 - 白; 色: 16250863

# Material: 硬質ウレタンフォーム
Identity - Category: 一般; Class: 一般; Description: 201
その他 - カテゴリ: マテリアル; 建材番号: 201
識別情報 - コメント: 201; 価格: 0; 説明: 硬質ウレタンフォーム
マテリアルと仕上げ - グロー: no; 透過度: 0; フラットさ: 50; 光沢: 64; 名前: 硬質ウレタンフォーム; 色: 15000804

# Material: アスファルト類
Identity - Category: 一般; Class: 一般; Description: 103
その他 - カテゴリ: マテリアル; 建材番号: 103
識別情報 - 価格: 0; 説明: アスファルト類
マテリアルと仕上げ - グロー: no; 透過度: 0; フラットさ: 50; 光沢: 64; 名前: アスファルト類; 色: 15000804

# Material: 非密閉中空層
Identity - Category: 一般; Class: 一般; Description: 302
その他 - カテゴリ: マテリアル; 建材番号: 302
識別情報 - コメント: 302; 価格: 0; 説明: 非密閉中空層
マテリアルと仕上げ - グロー: no; 透過度: 0; フラットさ: 50; 光沢: 64; 名前: 非密閉中空層; 色: 15000804

# Material: ロックウール化粧吸音板
Identity - Category: 一般; Class: 一般; Description: 70
その他 - カテゴリ: マテリアル; 建材番号: 70
識別情報 - コメント: 70; 価格: 0; 説明: ロックウール化粧吸音板
マテリアルと仕上げ - グロー: no; 透過度: 0; フラットさ: 50; 光沢: 64; 名前: ロックウール化粧吸音板; 色: 15000804

# Material: ガラス - 透明
Identity - Category: 未設定; Class: 未設定
その他 - カテゴリ: マテリアル
マテリアルと仕上げ - グロー: no; フラットさ: 50; 光沢: 12; 名前: ガラス - 透明; 色: 12615680; 透過度: 90
